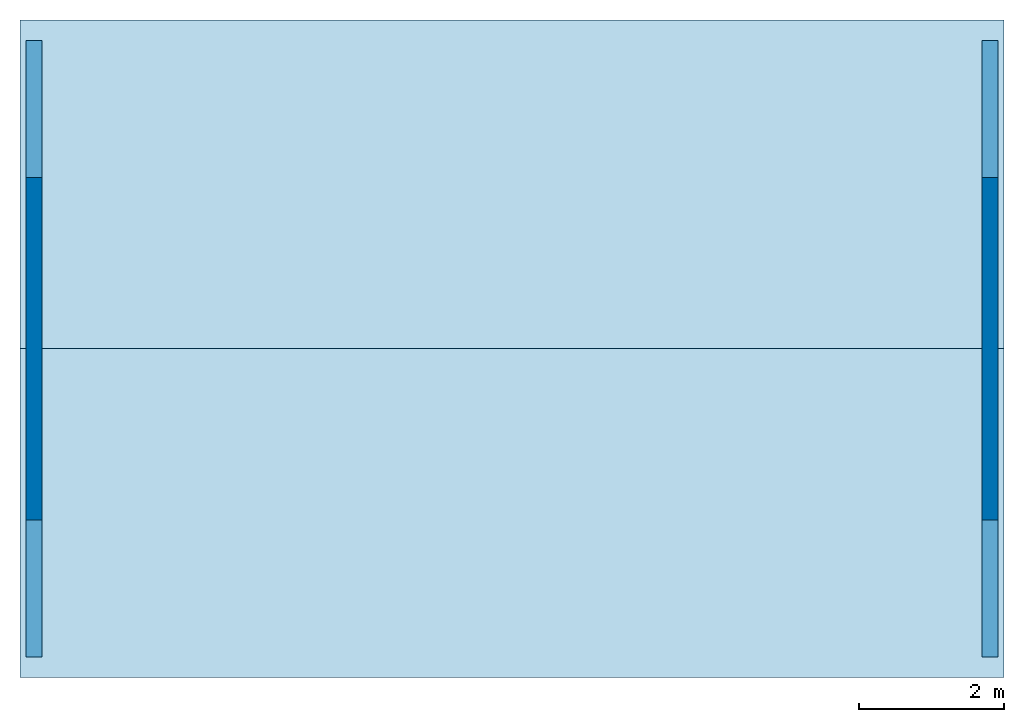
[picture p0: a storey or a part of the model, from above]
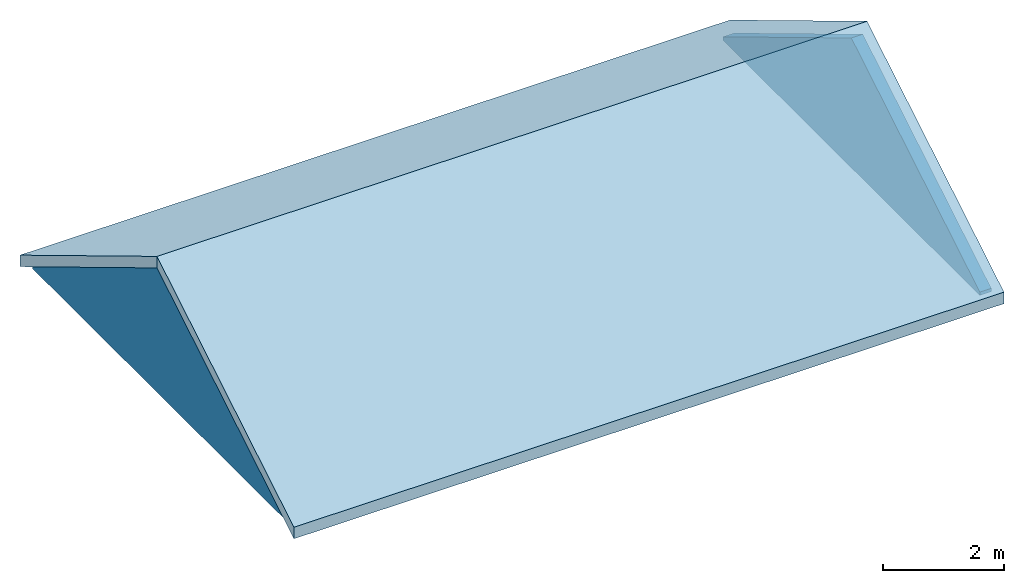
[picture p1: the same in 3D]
Properties of the parts of a building model (IFC2X3)

# File
Description: ViewDefinition [CoordinationView_V2.0]
Time: 2016-03-23T11:25:58
Written by: The EXPRESS Data Manager Version 5.02.0100.07 : 28 Aug 2013
Made in: 20150714_1515(x64) - Exporter 16.3.0.0 - Interface alternative d'export 16.3.0.0
Comment: STEP Physical File produced by: The EXPRESS Data Manager Version 5.02.0100.07 : 28 Aug 2013 * Module: EDMstepFileFactory/EDMstandAlone * Creation date: Wed Mar 23 11:25:58 2016 * Host: St�phaneBertran * Database: C:\Users\STPHAN~1\AppData\Local\Temp\{88E3332E-4D32-433F-B5D4-6F25A7565194}\ifc * Database version: 5507 * Database creation date: Wed Mar 23 11:25:18 2016 * Schema: IFC2X3 * Model: DataRepository.ifc * Model creation date: Wed Mar 23 11:25:19 2016 * Header model: DataRepository.ifc_HeaderModel * Header model creation date: Wed Mar 23 11:25:19 2016 * EDMuser: sdai-user * EDMgroup: sdai-group * License ID and type: 5605 : Permanent license. Expiry date: * EDMstepFileFactory options: 020000

# IfcProject
LongName: E:\02 Année scolaire 2015 2016\01 Seconde TEBEE\07 Projet Damparis\Travail demandé\Nouveau dossier\pavillon seul.ifc

# IfcSite, Surface:187648
RefLatitude: 48, 51, 23, 999632; RefLongitude: 2, 21, 3, 553904; RefElevation: 0 m

# IfcBuilding
Pset_BuildingCommon - NumberOfStoreys: 4

# IfcBuildingStorey (4)
Name | LongName | Elevation (m)
soubassement | soubassement | -0.6
Rez de chaussée | Rez de chaussée | 0
Plan étage | Plan étage | 2.74
Plan de couverture | Plan de couverture | 5.3

# IfcBeam: Poutre rectangulaire - Béton:200 x 400 mm:273551 (2)
In: Rez de chaussée
Material: Maçonnerie - Béton
Pset_BeamCommon - IsExternal: no; LoadBearing: yes; Reference: 200 x 400 mm; Span: 6.53 m; Slope: 0 deg
Name (Poutre rectangulaire - Béton:200 x 400 mm:...)
274924
275096

# IfcColumn: 200 x 200 mm (2)
Type - ElementType: 200 x 200 mm; PredefinedType: COLUMN; Material: Maçonnerie - Béton
Pset_ColumnCommon - LoadBearing: no; IsExternal: no; Reference: 200 x 200 mm
Name (Poteau rectangulaire:200 x 200 mm:...) | In
187471 | soubassement
187492 | Rez de chaussée

# IfcCovering: Plafond composé:Plafond avec isolation, Plafond composé:Plafond avec isolation:277230
In: Plan étage
PredefinedType: CEILING; Material: Maçonnerie - Isolant 0.25 m, Faux-plafond - Trame 600 x 600 0.01 m
Pset_CoveringCommon - Reference: Plafond avec isolation; TotalThickness: 0.26 m

# IfcDoor: PF 1.30 x 2.15 (3)
In: Rez de chaussée
Type - OperationType: DOUBLE_DOOR_SINGLE_SWING; ParameterTakesPrecedence: no; Sizeable: no; Classification: C1020 Interior Doors (Uniformat); Material: Glass, PVC - Blanc
Type - Double-Glass 1_no trim:PF 1.30 x 2.15:205899 - PanelOperation: SWINGING
OverallHeight: 2.15 m; OverallWidth: 1.3 m
Pset_DoorCommon - IsExternal: no; Reference: PF 1.30 x 2.15
Name (Double-Glass 1_no trim:PF 1.30 x 2.15:...)
205899
205926
205958

# IfcDoor: PF 1.30 x 2.15, Double-Glass 1_no trim:PF 1.30 x 2.15:206001
In: Rez de chaussée
Type - OperationType: DOUBLE_DOOR_SINGLE_SWING; ParameterTakesPrecedence: no; Sizeable: no; Classification: C1020 Interior Doors (Uniformat); Material: Glass, PVC - Blanc
Type - Double-Glass 1_no trim:PF 1.30 x 2.15:206001 - PanelOperation: SWINGING
OverallHeight: 2.15 m; OverallWidth: 1.3 m
Pset_DoorCommon - IsExternal: no; Reference: PF 1.30 x 2.15

# IfcDoor: PF 1.60 x 2.15 (2)
In: Rez de chaussée
Type - OperationType: DOUBLE_DOOR_SINGLE_SWING; ParameterTakesPrecedence: no; Sizeable: no; Classification: C1020 Interior Doors (Uniformat); Material: Glass, PVC - Blanc
Type - Double-Glass 1_no trim:PF 1.60 x 2.15:205161 - PanelOperation: SWINGING
OverallHeight: 2.15 m; OverallWidth: 1.6 m
Pset_DoorCommon - IsExternal: no; Reference: PF 1.60 x 2.15
Name (Double-Glass 1_no trim:PF 1.60 x 2.15:...)
205161
205435

# IfcDoor: PP (0.83m x 2.04m) (5)
Type - OperationType: SINGLE_SWING_LEFT; ParameterTakesPrecedence: no; Sizeable: no; Material: Finition Peinture - Blanc satiné, Bois - Panneau de porte, Bois - Cadre de porte
Type - Int. Simple:PP (0.83m x 2.04m):187630 - PanelOperation: SWINGING
OverallHeight: 2.075 m; OverallWidth: 0.9 m
Pset_DoorCommon - IsExternal: no; Reference: PP (0.83m x 2.04m)
Name (Int. Simple:PP (0.83m x 2.04m):...) | In
187630 | Plan étage
187632 | Plan étage
187636 | Plan étage
187641 | Plan étage
206475 | Rez de chaussée

# IfcDoor: PP (0.83m x 2.04m), Int. Simple:PP (0.83m x 2.04m):187644
In: Plan étage
Type - OperationType: SINGLE_SWING_LEFT; ParameterTakesPrecedence: no; Sizeable: no; Material: Finition Peinture - Blanc satiné, Bois - Panneau de porte, Bois - Cadre de porte
Type - Int. Simple:PP (0.83m x 2.04m):187644 - PanelOperation: SWINGING
OverallHeight: 2.075 m; OverallWidth: 0.9 m
Pset_DoorCommon - IsExternal: no; Reference: PP (0.83m x 2.04m)

# IfcDoor: PP (0.83m x 2.04m), Int. Simple:PP (0.83m x 2.04m):206517
In: Rez de chaussée
Type - OperationType: SINGLE_SWING_LEFT; ParameterTakesPrecedence: no; Sizeable: no; Material: Finition Peinture - Blanc satiné, Bois - Panneau de porte, Bois - Cadre de porte
Type - Int. Simple:PP (0.83m x 2.04m):206517 - PanelOperation: SWINGING
OverallHeight: 2.075 m; OverallWidth: 0.9 m
Pset_DoorCommon - IsExternal: no; Reference: PP (0.83m x 2.04m)

# IfcDoor: PP (0.83m x 2.04m), Int. Simple:PP (0.83m x 2.04m):206587
In: Rez de chaussée
Type - OperationType: SINGLE_SWING_LEFT; ParameterTakesPrecedence: no; Sizeable: no; Material: Finition Peinture - Blanc satiné, Bois - Panneau de porte, Bois - Cadre de porte
Type - Int. Simple:PP (0.83m x 2.04m):206587 - PanelOperation: SWINGING
OverallHeight: 2.075 m; OverallWidth: 0.9 m
Pset_DoorCommon - IsExternal: no; Reference: PP (0.83m x 2.04m)

# IfcDoor: PP (0.83m x 2.04m) (6)
Type - OperationType: SINGLE_SWING_RIGHT; ParameterTakesPrecedence: no; Sizeable: no; Material: Finition Peinture - Blanc satiné, Bois - Panneau de porte, Bois - Cadre de porte
Type - Int. Simple:PP (0.83m x 2.04m):187629 - PanelOperation: SWINGING
OverallHeight: 2.075 m; OverallWidth: 0.9 m
Pset_DoorCommon - IsExternal: no; Reference: PP (0.83m x 2.04m)
Name (Int. Simple:PP (0.83m x 2.04m):...) | In
187629 | Plan étage
187631 | Plan étage
187635 | Plan étage
187647 | Plan étage
206419 | Rez de chaussée
206630 | Rez de chaussée

# IfcDoor: PP (0.83m x 2.04m) (2)
Type - OperationType: SINGLE_SWING_RIGHT; ParameterTakesPrecedence: no; Sizeable: no; Material: Finition Peinture - Blanc satiné, Bois - Panneau de porte, Bois - Cadre de porte
Type - Int. Simple:PP (0.83m x 2.04m):187633 - PanelOperation: SWINGING
OverallHeight: 2.075 m; OverallWidth: 0.9 m
Pset_DoorCommon - IsExternal: no; Reference: PP (0.83m x 2.04m)
Name (Int. Simple:PP (0.83m x 2.04m):...) | In
187633 | Plan étage
206556 | Rez de chaussée

# IfcDoor: PP Lisse (0.90m x 2.15m), Porte d'entrée:PP Lisse (0.90m x 2.15m):187528
In: Rez de chaussée
Type - OperationType: SINGLE_SWING_LEFT; ParameterTakesPrecedence: no; Sizeable: no; Material: Porte d'entrée - Poignée, Porte d'entrée - Panneau, Porte d'entrée - Cadre
Type - Porte d'entrée:PP Lisse (0.90m x 2.15m):187528 - PanelOperation: SWINGING
OverallHeight: 2.19 m; OverallWidth: 0.98 m
Pset_DoorCommon - IsExternal: no; Reference: PP Lisse (0.90m x 2.15m)

# IfcDoor: PP Lisse (0.90m x 2.15m), Porte d'entrée:PP Lisse (0.90m x 2.15m):205515
In: Rez de chaussée
Type - OperationType: SINGLE_SWING_RIGHT; ParameterTakesPrecedence: no; Sizeable: no; Material: Porte d'entrée - Poignée, Porte d'entrée - Panneau, Porte d'entrée - Cadre
Type - Porte d'entrée:PP Lisse (0.90m x 2.15m):205515 - PanelOperation: SWINGING
OverallHeight: 2.19 m; OverallWidth: 0.98 m
Pset_DoorCommon - IsExternal: no; Reference: PP Lisse (0.90m x 2.15m)

# IfcDoor: Placard coulissante - 3 panneaux (2)
In: Rez de chaussée
Type - OperationType: SLIDING_TO_RIGHT; ParameterTakesPrecedence: no; Sizeable: no; Material: Placard - Profil, Placard - Encadrement, Placard - Porte
Type - Placard coulissante - 3 panneaux:Placard coulissante - 3 panneaux:187537 - PanelOperation: SLIDING
OverallHeight: 2.1 m; OverallWidth: 1.7 m
Pset_DoorCommon - IsExternal: no; Reference: Placard coulissante - 3 panneaux
Name (Placard coulissante - 3 panneaux:Placard coulissante - 3 panneaux:...)
187537
204080

# IfcRailing: Garde-corps:Type Bateau (3)
In: Rez de chaussée
Material: Peinture - grise, Bois - Pin
Pset_RailingCommon - IsExternal: no; Reference: Type Bateau; Height: 1.2192 m
Name (Garde-corps:Type Bateau:...)
223490
227138
271948

# IfcRoof: Toit de base:Toit - 200 mm, Toit de base:Toit - 200 mm:277896
In: Plan de couverture
Pset_RoofCommon - IsExternal: yes; Reference: Toit - 200 mm; TotalArea: 143.325 m2; ProjectedArea: 122.854 m2

# IfcSlab: Base rectangulaire:1000mm x 1000mm x 300mm (2)
In: soubassement
PredefinedType: FLOOR; Material: Béton - Béton coulé sur place
Pset_SlabCommon - IsExternal: no; LoadBearing: yes; PitchAngle: 0 deg; Reference: 1000mm x 1000mm x 300mm
Name (Base rectangulaire:1000mm x 1000mm x 300mm:...)
215258
215662

# IfcSlab: Base rectangulaire:1500mm x 1000mm x 300mm (6)
In: soubassement
PredefinedType: FLOOR; Material: Béton - Béton coulé sur place
Pset_SlabCommon - IsExternal: no; LoadBearing: yes; Reference: 1500mm x 1000mm x 300mm; PitchAngle: 0 deg
Name (Base rectangulaire:1500mm x 1000mm x 300mm:...)
213384
213606
213688
213876
214012
214106

# IfcSlab: Base rectangulaire:800mm x 1000mm x 300mm (3)
In: soubassement
PredefinedType: FLOOR; Material: Béton - Béton coulé sur place
Pset_SlabCommon - IsExternal: no; LoadBearing: yes; PitchAngle: 0 deg; Reference: 800mm x 1000mm x 300mm
Name (Base rectangulaire:800mm x 1000mm x 300mm:...)
214496
214606
214724

# IfcSlab: Base rectangulaire:gros beton 1000mm x 1000mm x 1190mm (2)
In: soubassement
PredefinedType: FLOOR; Material: Béton - Béton coulé sur place
Pset_SlabCommon - IsExternal: no; LoadBearing: yes; PitchAngle: 0 deg; Reference: gros beton 1000mm x 1000mm x 1190mm
Name (Base rectangulaire:gros beton 1000mm x 1000mm x 1190mm:...)
216552
216665

# IfcSlab: Base rectangulaire:gros beton 1000mm x 800mm x 1190mm (2)
In: soubassement
PredefinedType: FLOOR; Material: Béton - Béton coulé sur place
Pset_SlabCommon - IsExternal: no; LoadBearing: yes; PitchAngle: 0 deg; Reference: gros beton 1000mm x 800mm x 1190mm
Name (Base rectangulaire:gros beton 1000mm x 800mm x 1190mm:...)
218791
218905

# IfcSlab: Base rectangulaire:gros beton 1000mm x 800mm x 590mm, Base rectangulaire:gros beton 1000mm x 800mm x 590mm:218621
In: soubassement
PredefinedType: FLOOR; Material: Béton - Béton coulé sur place
Pset_SlabCommon - IsExternal: no; LoadBearing: yes; PitchAngle: 0 deg; Reference: gros beton 1000mm x 800mm x 590mm

# IfcSlab: Base rectangulaire:gros beton 1500mm x 1000mm x 1190mm (4)
In: soubassement
PredefinedType: FLOOR; Material: Béton - Béton coulé sur place
Pset_SlabCommon - IsExternal: no; LoadBearing: yes; PitchAngle: 0 deg; Reference: gros beton 1500mm x 1000mm x 1190mm
Name (Base rectangulaire:gros beton 1500mm x 1000mm x 1190mm:...)
217089
217251
217483
218347

# IfcSlab: Base rectangulaire:gros beton 1500mm x 1000mm x 590mm (2)
In: soubassement
PredefinedType: FLOOR; Material: Béton - Béton coulé sur place
Pset_SlabCommon - IsExternal: no; LoadBearing: yes; PitchAngle: 0 deg; Reference: gros beton 1500mm x 1000mm x 590mm
Name (Base rectangulaire:gros beton 1500mm x 1000mm x 590mm:...)
216937
217617

# IfcSlab: Sol:Dalle Béton -160 + 60 mm, Sol:Dalle Béton -160 + 60 mm:276078
In: Plan étage
PredefinedType: FLOOR; Material: <Unnamed> 0.01 m, Maçonnerie - Béton 0.22 m, <Unnamed> 0.01 m
Pset_SlabCommon - IsExternal: no; LoadBearing: yes; PitchAngle: 0 deg; Reference: Dalle Béton -160 + 60 mm

# IfcSlab: Sol:Dalle en béton - 13 (2)
In: Rez de chaussée
PredefinedType: FLOOR; Material: Maçonnerie - Béton 0.13 m, Maçonnerie - Isolant 1 0.08 m
Pset_SlabCommon - IsExternal: no; LoadBearing: yes; PitchAngle: 0 deg; Reference: Dalle en béton - 13
Name (Sol:Dalle en béton - 13:...)
219665
220152

# IfcSlab: Toit de base:Toit - 200 mm (2)
In: Plan de couverture
PredefinedType: ROOF; Material: Toit par défaut 0.2 m
Pset_SlabCommon - LoadBearing: yes; IsExternal: yes; Reference: Toit - 200 mm; PitchAngle: 31 deg

# IfcStair: Escalier:Monobloc:28673 (5)
In: Rez de chaussée
Name (Escalier:Monobloc:...) | IsExternal | Reference | NumberOfRiser = NumberOfTreads | RiserHeight (m) | TreadLength (m)
223436 | no | Monobloc | 12 | 0.182667 | 0.264667
225808 | Material: Maçonnerie - Béton
225808 | no | Monobloc | 15 | 0.182667 | 0.264667
271926 | Material: Maçonnerie - Béton
271926 | no | Monobloc | 15 | 0.182667 | 0.264667

# IfcWallStandardCase: Mur de base:Ext. longrine 20 x 60 (5)
In: soubassement
Type - PredefinedType: STANDARD; Material: Maçonnerie - Voile BA 0.2 m
Pset_WallCommon - ExtendToStructure: no; LoadBearing: yes; IsExternal: yes; Reference: Ext. longrine 20 x 60
Name (Mur de base:Ext. longrine 20 x 60:...)
212326
212358
212399
212434
212556

# IfcWallStandardCase: Mur de base:Int. plâtre 50 mm (34)
Type - PredefinedType: STANDARD; Material: Maçonnerie - Isolant(1) 0.05 m
Pset_WallCommon - Reference: Int. plâtre 50 mm; LoadBearing: no; ExtendToStructure: no; IsExternal: no
Name (Mur de base:Int. plâtre 50 mm:...) | In
187323 | Rez de chaussée
187338 | Rez de chaussée
187425 | Rez de chaussée
187440 | Rez de chaussée
187517 | Rez de chaussée
187518 | Rez de chaussée
187519 | Rez de chaussée
187520 | Rez de chaussée
187521 | Rez de chaussée
187522 | Rez de chaussée
187531 | Rez de chaussée
187532 | Rez de chaussée
187533 | Rez de chaussée
187534 | Rez de chaussée
187535 | Rez de chaussée
187536 | Rez de chaussée
187620 | Plan étage
187621 | Plan étage
187622 | Plan étage
187623 | Plan étage
187624 | Plan étage
187625 | Plan étage
187626 | Plan étage
187627 | Plan étage
187628 | Plan étage
187634 | Plan étage
187637 | Plan étage
187638 | Plan étage
187639 | Plan étage
187640 | Plan étage
187642 | Plan étage
187643 | Plan étage
187645 | Plan étage
187646 | Plan étage

# IfcWallStandardCase: Mur de base:Mur de base Ext. Parpaing 20 (2)
In: Plan de couverture
Type - PredefinedType: STANDARD; Material: Maçonnerie - Enduit 0.02 m, Maçonnerie - Parpaing 0.2 m
Pset_WallCommon - LoadBearing: yes; IsExternal: yes; Reference: Mur de base Ext. Parpaing 20; ExtendToStructure: yes
Name (Mur de base:Mur de base Ext. Parpaing 20:...)
278254
278265

# IfcWallStandardCase: Mur de base:Mur de base Ext. Parpaing 20 + Isolant 12 (8)
Type - PredefinedType: STANDARD; Material: Maçonnerie - Enduit 0.02 m, Maçonnerie - Parpaing 0.2 m, Maçonnerie - Isolant 0.11 m, Maçonnerie - Isolant 1 0.01 m
Pset_WallCommon - ExtendToStructure: no; Reference: Mur de base Ext. Parpaing 20 + Isolant 12; LoadBearing: yes; IsExternal: yes
Name (Mur de base:Mur de base Ext. Parpaing 20 + Isolant 12:...) | In
187353 | Rez de chaussée
187389 | Rez de chaussée
187494 | Rez de chaussée
187495 | Rez de chaussée
187561 | Plan étage
187583 | Plan étage
188922 | Plan étage
188923 | Plan étage

# IfcWallStandardCase: Mur de base:Mur de base Refend Ext. Parpaing 20 + Isolant 7 (2)
Type - PredefinedType: STANDARD; Material: Maçonnerie - Isolant 1 0.01 m, Maçonnerie - Bloc de béton (2) 0.2 m, Maçonnerie - Isolant 0.06 m, Maçonnerie - Isolant 1 0.01 m
Pset_WallCommon - ExtendToStructure: no; LoadBearing: yes; IsExternal: yes; Reference: Mur de base Refend Ext. Parpaing 20 + Isolant 7
Name (Mur de base:Mur de base Refend Ext. Parpaing 20 + Isolant 7:...) | In
187506 | Rez de chaussée
187610 | Plan étage

# IfcWindow: 60x65 (2)
In: Plan étage
Type - ParameterTakesPrecedence: no; Sizeable: no; Material: Appui, Huisserie, Verre
OverallHeight: 0.959972 m; OverallWidth: 0.7 m
Pset_WindowCommon - IsExternal: yes; Reference: 60x65
Name (FR_1 Vantail Appui Béton:60x65:...)
190471
220469

# IfcWindow: 90x135 (6)
In: Plan étage
Type - ParameterTakesPrecedence: no; Sizeable: no; Material: Appui, Huisserie, Verre
OverallHeight: 1.65997 m; OverallWidth: 1 m
Pset_WindowCommon - IsExternal: yes; Reference: 90x135
Name (FR_1 Vantail Appui Béton:90x135:...)
190443
220285
220312
220338
220372
220425
